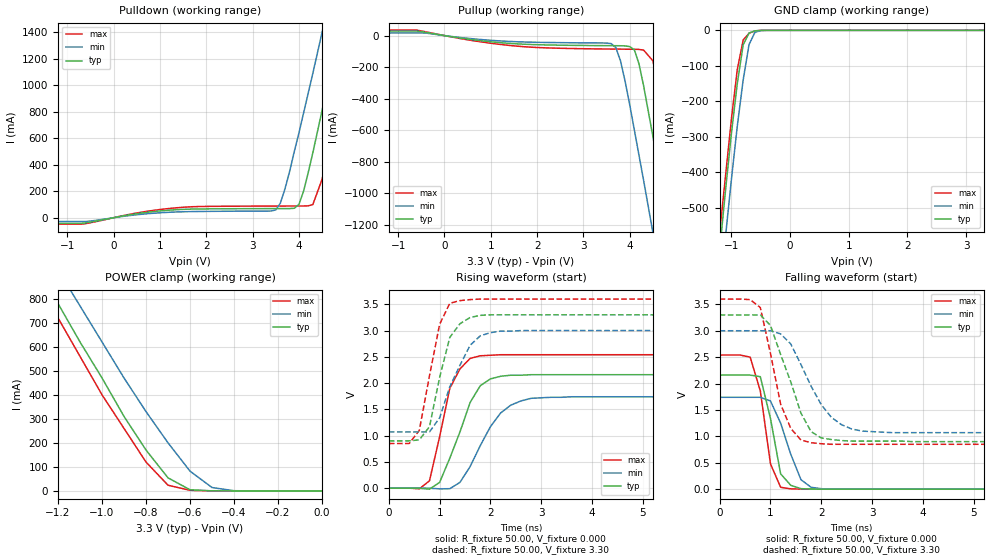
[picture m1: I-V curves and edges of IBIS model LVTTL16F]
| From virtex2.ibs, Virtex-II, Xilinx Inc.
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|   Model LVTTL16F
[Model]   LVTTL16F
Model_type   I/O
Polarity   Non-Inverting
Enable   Active-Low
Vinh = 2.0V
Vinl = 0.8V
Vmeas =   1.40V
Cref =  0pF
Rref =   1.00M
Vref =  0.000V
C_comp   10.00pF   10.00pF   10.00pF
[Temperature Range]   25.00   100.00   0.000
[Voltage Range]   3.30V   3.00V   3.60V
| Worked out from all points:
|   slope of the pulldown table from 0 to 0.495 V, typ, clamps not added: 16.5 ohm
|   slope of the pullup table from 0 to 0.495 V, typ, clamps not added: 22.7 ohm
|   GND clamp passes 1 mA (typ) near -0.57 V on its own axis
|   POWER clamp passes 1 mA (typ) near -0.52 V on its own axis
|   rising waveform, R_fixture 50.00, V_fixture 0.000: 20-80 % time 521ps typ, 612ps min, 384ps max; typ from 0 V to 2.16 V
|   rising waveform, R_fixture 50.00, V_fixture 3.30: 20-80 % time 342ps typ, 505ps min, 328ps max; typ from 0.9 V to 3.3 V
|   falling waveform, R_fixture 50.00, V_fixture 0.000: 20-80 % time 271ps typ, 398ps min, 250ps max; typ from 2.16 V to 0 V
|   falling waveform, R_fixture 50.00, V_fixture 3.30: 20-80 % time 532ps typ, 650ps min, 402ps max; typ from 3.3 V to 0.9 V
[Pulldown]
| voltage   I(typ)   I(min)   I(max)
-3.3V     -42.66mA   -28.71mA   -48.88mA
-700mV    -42.66mA   -28.71mA   -48.88mA
1.3V      59.43mA    42.7mA     73.14mA
3.5V      68.88mA    58.81mA    88.01mA
3.7V      69.04mA    220mA      88.18mA
4V        100mA      640mA      88.42mA
4.3V      490mA      1.09A      98.99mA
4.5V      810mA      1.4A       290mA
4.9V      1.45A      2.03A      910mA
5.1V      1.78A      2.34A      1.24A
5.3V      2.11A      2.66A      1.56A
6.6V      4.28A      4.72A      3.72A
[Pullup]
| voltage   I(typ)   I(min)   I(max)
-3.3V     28.6mA     16.68mA    34.69mA
-600mV    28.6mA     16.68mA    34.69mA
3.6V      -63.99mA   -50.9mA    -85.36mA
3.8V      -64.43mA   -160mA     -85.91mA
4.1V      -90.87mA   -600mA     -86.68mA
4.3V      -320mA     -920mA     -92.25mA
4.5V      -640mA     -1.25A     -160mA
4.7V      -980mA     -1.59A     -440mA
4.9V      -1.32A     -1.93A     -770mA
5.1V      -1.67A     -2.27A     -1.11A
5.3V      -2.02A     -2.61A     -1.46A
6.6V      -4.32A     -4.85A     -3.75A
[GND_clamp]
| voltage   I(typ)   I(min)   I(max)
-3.3V     -4.3A      -4.31A     -4.26A
-1.2V     -620mA     -740mA     -570mA
-1.1V     -450mA     -580mA     -410mA
-1V       -290mA     -420mA     -250mA
-900mV    -150mA     -270mA     -110mA
-800mV    -41.03mA   -140mA     -27.28mA
-700mV    -7.6mA     -40.21mA   -8.18mA
-600mV    -1.42mA    -5.61mA    -1.62mA
-500mV    -130uA     -670uA     -130uA
3.3V      67.85pA    43.48uA    45.6pA
[POWER_clamp]
| voltage   I(typ)   I(min)   I(max)
-3.3V     4.25A      4.22A      4.2A
-1.3V     940mA      1.07A      880mA
-1.2V     780mA      920mA      720mA
-1.1V     620mA      770mA      560mA
-1V       470mA      620mA      400mA
-900mV    310mA      470mA      260mA
-800mV    170mA      330mA      120mA
-700mV    54.34mA    200mA      23.62mA
-600mV    4.76mA     82.21mA    2.52mA
-500mV    280uA      14.02mA    260uA
-400mV    16.9uA     860uA      14.85uA
0V        67.85pA    2.04nA     61.89pA
[Ramp]
| variable   typ   min   max
dV/dt_r   1.29/0.44n   1.04/0.60n   1.52/0.34n
dV/dt_f   1.44/0.46n   1.16/0.64n   1.65/0.35n
R_load = 50.00
[Rising Waveform]
R_fixture = 50.00
V_fixture = 0.000
| time   V(typ)   V(min)   V(max)
0s        0V         0V         0V
600ps     -3.08mV    20.39uV    -12.83mV
800ps     -19.44mV   -1.58mV    140mV
1ns       110mV      -13.7mV    980mV
1.2ns     570mV      -10.5mV    1.9V
1.6ns     1.63V      410mV      2.47V
1.8ns     1.95V      810mV      2.52V
2.2ns     2.13V      1.43V      2.54V
2.8ns     2.16V      1.71V      2.54V
10ns      2.16V      1.74V      2.54V
[Rising Waveform]
R_fixture = 50.00
V_fixture = 3.30
V_fixture_min = 3.00
V_fixture_max = 3.60
| time   V(typ)   V(min)   V(max)
0s        900mV      1.07V      850mV
400ps     900mV      1.07V      850mV
600ps     920mV      1.07V      1.1V
800ps     1.17V      1.07V      2.14V
1ns       2.11V      1.34V      3.12V
1.2ns     2.87V      1.93V      3.52V
1.6ns     3.25V      2.72V      3.59V
1.8ns     3.29V      2.9V       3.6V
2.2ns     3.3V       2.99V      3.6V
10ns      3.3V       3V         3.6V
[Falling Waveform]
R_fixture = 50.00
V_fixture = 0.000
| time   V(typ)   V(min)   V(max)
0s        2.16V      1.74V      2.54V
600ps     2.16V      1.74V      2.5V
800ps     2.13V      1.74V      1.86V
1ns       1.34V      1.67V      480mV
1.2ns     290mV      1.25V      34.97mV
1.4ns     72.7mV     660mV      6.23mV
1.6ns     9.68mV     180mV      1.58mV
1.8ns     2.28mV     35.69mV    600uV
2.4ns     220uV      1.24mV     56.85uV
10ns      1.37uV     2.96uV     4.37uV
[Falling Waveform]
R_fixture = 50.00
V_fixture = 3.30
V_fixture_min = 3.00
V_fixture_max = 3.60
| time   V(typ)   V(min)   V(max)
0s        3.3V       3V         3.6V
800ps     3.3V       3V         3.44V
1ns       3.1V       3V         2.57V
1.2ns     2.55V      2.94V      1.61V
1.4ns     2.03V      2.75V      1.15V
1.6ns     1.44V      2.36V      930mV
1.8ns     1.09V      1.95V      880mV
2.2ns     940mV      1.36V      850mV
2.8ns     910mV      1.1V       850mV
10ns      900mV      1.07V      850mV
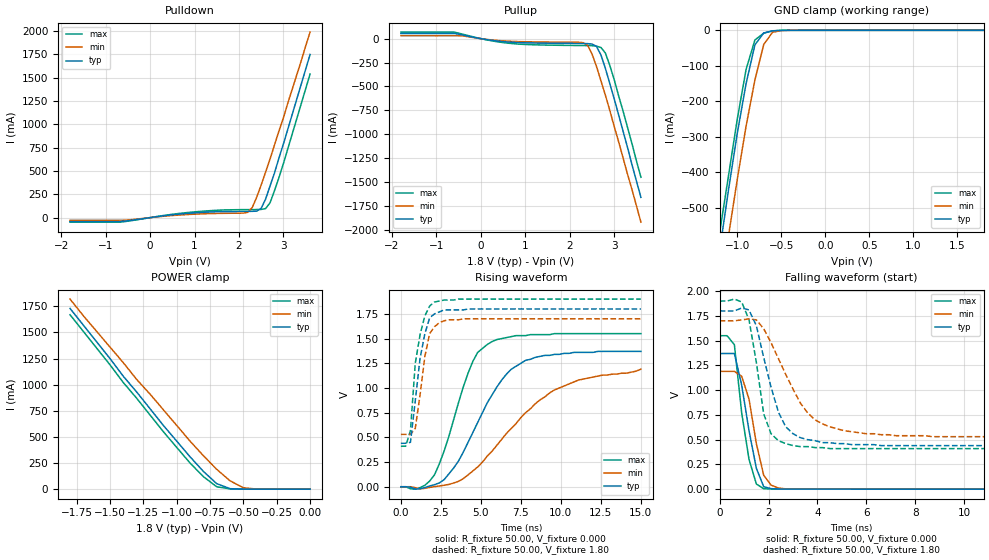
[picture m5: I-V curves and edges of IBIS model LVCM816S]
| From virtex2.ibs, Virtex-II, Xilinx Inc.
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|   Model LVCM816S
[Model]   LVCM816S
Model_type   I/O
Polarity   Non-Inverting
Enable   Active-Low
Vinh = 1.19V
Vinl = 0.4V
Vmeas =   0.90V
Cref =  0pF
Rref =   1.00M
Vref =  0.000V
C_comp   10.00pF   10.00pF   10.00pF
[Temperature Range]   25.00   100.00   0.000
[Voltage Range]   1.80V   1.70V   1.90V
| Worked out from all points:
|   slope of the pulldown table from 0 to 0.27 V, typ, clamps not added: 15.4 ohm
|   slope of the pullup table from 0 to 0.27 V, typ, clamps not added: 14.2 ohm
|   GND clamp passes 1 mA (typ) near -0.57 V on its own axis
|   POWER clamp passes 1 mA (typ) near -0.52 V on its own axis
|   rising waveform, R_fixture 50.00, V_fixture 0.000: 20-80 % time 2.73ns typ, 4.29ns min, 1.84ns max; typ from 0 V to 1.37 V
|   rising waveform, R_fixture 50.00, V_fixture 1.80: 20-80 % time 686ps typ, 637ps min, 637ps max; typ from 0.44 V to 1.8 V
|   falling waveform, R_fixture 50.00, V_fixture 0.000: 20-80 % time 593ps typ, 563ps min, 498ps max; typ from 1.37 V to 0 V
|   falling waveform, R_fixture 50.00, V_fixture 1.80: 20-80 % time 922ps typ, 1.5ns min, 603ps max; typ from 1.8 V to 0.44 V
[Pulldown]
| voltage   I(typ)   I(min)   I(max)
-1.8V     -42.66mA   -28.72mA   -48.89mA
-700mV    -42.66mA   -28.72mA   -48.89mA
900mV     47.73mA    34.88mA    57.36mA
2.2V      67.2mA     56.66mA    86.05mA
2.3V      67.54mA    110mA      86.33mA
2.4V      69.73mA    220mA      86.66mA
2.5V      99.28mA    350mA      87.97mA
2.6V      200mA      490mA      97.08mA
2.7V      340mA      630mA      160mA
2.9V      640mA      930mA      430mA
3V        790mA      1.07A      580mA
3.6V      1.75A      1.99A      1.54A
[Pullup]
| voltage   I(typ)   I(min)   I(max)
-1.8V     54.35mA    30.98mA    68.67mA
-600mV    54.35mA    30.98mA    68.67mA
100mV     -7.7mA     -5.89mA    -9.92mA
700mV     -37.83mA   -28.42mA   -51.54mA
2.2V      -50.35mA   -38.05mA   -71.67mA
2.4V      -51.79mA   -68.88mA   -72.53mA
2.5V      -56.69mA   -160mA     -73.67mA
2.6V      -79.92mA   -290mA     -78.72mA
2.7V      -170mA     -440mA     -91.95mA
2.8V      -310mA     -590mA     -150mA
3V        -630mA     -920mA     -430mA
3.6V      -1.66A     -1.92A     -1.45A
[GND_clamp]
| voltage   I(typ)   I(min)   I(max)
-1.8V     -1.65A     -1.74A     -1.6A
-1.2V     -620mA     -740mA     -570mA
-1.1V     -450mA     -580mA     -410mA
-1V       -290mA     -420mA     -250mA
-900mV    -150mA     -270mA     -110mA
-800mV    -40.97mA   -140mA     -27.17mA
-700mV    -7.54mA    -40.17mA   -8.08mA
-600mV    -1.39mA    -5.57mA    -1.57mA
-500mV    -120uA     -660uA     -120uA
1.8V      34.27pA    98.88nA    22.46pA
[POWER_clamp]
| voltage   I(typ)   I(min)   I(max)
-1.8V     1.73A      1.82A      1.67A
-1.7V     1.57A      1.66A      1.51A
-1.4V     1.08A      1.21A      1.02A
-1.3V     930mA      1.05A      870mA
-1.1V     610mA      760mA      550mA
-900mV    310mA      460mA      250mA
-800mV    170mA      320mA      120mA
-700mV    52.75mA    190mA      22.81mA
-600mV    4.57mA     79.88mA    2.44mA
-500mV    270uA      13.45mA    250uA
-400mV    16.38uA    820uA      14.46uA
0V        34.27pA    1.07nA     29.84pA
[Ramp]
| variable   typ   min   max
dV/dt_r   0.82/2.72n   0.70/4.14n   0.93/1.83n
dV/dt_f   0.82/0.93n   0.70/1.50n   0.90/0.65n
R_load = 50.00
[Rising Waveform]
R_fixture = 50.00
V_fixture = 0.000
| time   V(typ)   V(min)   V(max)
0s        0V         0V         0V
1.2ns     -20.49mV   -22.42mV   -9mV
2.1ns     20.46mV    1.07mV     120mV
3.3ns     190mV      37.59mV    680mV
4.2ns     450mV      120mV      1.15V
5.4ns     850mV      310mV      1.44V
6.6ns     1.14V      540mV      1.51V
7.8ns     1.28V      750mV      1.53V
11.1ns    1.36V      1.08V      1.55V
15ns      1.37V      1.19V      1.55V
[Rising Waveform]
R_fixture = 50.00
V_fixture = 1.80
V_fixture_min = 1.70
V_fixture_max = 1.90
| time   V(typ)   V(min)   V(max)
0s        440mV      530mV      410mV
300ps     440mV      530mV      410mV
600ps     450mV      530mV      570mV
900ps     870mV      590mV      1.25V
1.2ns     1.3V       930mV      1.54V
1.5ns     1.55V      1.32V      1.73V
1.8ns     1.71V      1.55V      1.83V
2.1ns     1.75V      1.62V      1.87V
3.9ns     1.79V      1.7V       1.9V
15ns      1.8V       1.7V       1.9V
[Falling Waveform]
R_fixture = 50.00
V_fixture = 0.000
| time   V(typ)   V(min)   V(max)
0s        1.37V      1.19V      1.55V
300ps     1.37V      1.19V      1.55V
600ps     1.37V      1.19V      1.46V
900ps     1.05V      1.14V      770mV
1.2ns     590mV      910mV      300mV
1.5ns     210mV      460mV      51.81mV
1.8ns     24.76mV    140mV      4.54mV
2.1ns     5.13mV     41.39mV    1.83mV
2.7ns     1.59mV     3.14mV     1.2mV
15ns      -27.08uV   -24.9uV    32.58uV
[Falling Waveform]
R_fixture = 50.00
V_fixture = 1.80
V_fixture_min = 1.70
V_fixture_max = 1.90
| time   V(typ)   V(min)   V(max)
0s        1.8V       1.7V       1.9V
900ps     1.83V      1.71V      1.89V
1.2ns     1.81V      1.72V      1.71V
1.5ns     1.65V      1.71V      1.28V
1.8ns     1.33V      1.62V      760mV
2.1ns     1.03V      1.48V      560mV
2.7ns     630mV      1.16V      460mV
3.6ns     500mV      770mV      430mV
5.1ns     460mV      590mV      410mV
15ns      440mV      530mV      410mV
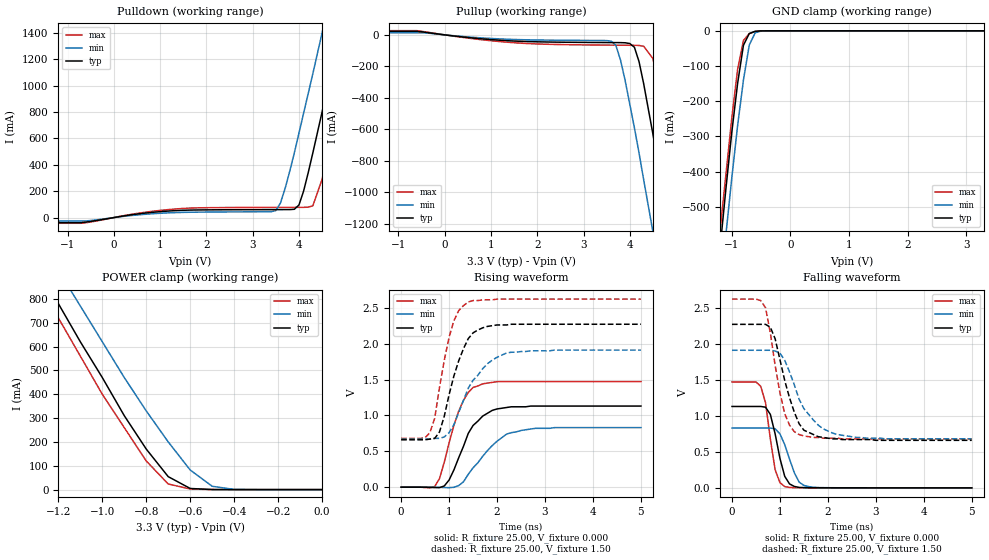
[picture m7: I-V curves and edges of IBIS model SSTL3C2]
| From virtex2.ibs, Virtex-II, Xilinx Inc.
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|   Model SSTL3C2
[Model]   SSTL3C2
Model_type   I/O
Polarity   Non-Inverting
Enable   Active-Low
Vinh = 1.7V
Vinl = 1.3V
Vmeas =   1.50V
Cref =  0pF
Rref =  25.00
Vref =   1.50V
C_comp   10.00pF   10.00pF   10.00pF
[Temperature Range]   25.00   100.00   0.000
[Voltage Range]   3.30V   3.00V   3.60V
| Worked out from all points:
|   slope of the pulldown table from 0 to 0.495 V, typ, clamps not added: 18.7 ohm
|   slope of the pullup table from 0 to 0.495 V, typ, clamps not added: 29.6 ohm
|   GND clamp passes 1 mA (typ) near -0.57 V on its own axis
|   POWER clamp passes 1 mA (typ) near -0.52 V on its own axis
|   rising waveform, R_fixture 25.00, V_fixture 0.000: 20-80 % time 483ps typ, 661ps min, 402ps max; typ from 0 V to 1.13 V
|   rising waveform, R_fixture 25.00, V_fixture 1.50: 20-80 % time 416ps typ, 589ps min, 337ps max; typ from 0.66 V to 2.27 V
|   falling waveform, R_fixture 25.00, V_fixture 0.000: 20-80 % time 231ps typ, 277ps min, 189ps max; typ from 1.13 V to 0 V
|   falling waveform, R_fixture 25.00, V_fixture 1.50: 20-80 % time 400ps typ, 554ps min, 310ps max; typ from 2.27 V to 0.66 V
[Pulldown]
| voltage   I(typ)   I(min)   I(max)
-3.3V     -37.48mA   -25.2mA    -43mA
-700mV    -37.48mA   -25.2mA    -43mA
1.3V      52.15mA    37.43mA    64.25mA
3.5V      60.35mA    53.12mA    77.14mA
3.7V      60.49mA    220mA      77.29mA
4V        95.25mA    640mA      77.5mA
4.3V      490mA      1.09A      89.15mA
4.5V      800mA      1.4A       290mA
4.9V      1.45A      2.02A      910mA
5.1V      1.78A      2.34A      1.23A
5.3V      2.11A      2.65A      1.56A
6.6V      4.27A      4.71A      3.72A
[Pullup]
| voltage   I(typ)   I(min)   I(max)
-3.3V     21.9mA     12.73mA    26.65mA
-600mV    21.9mA     12.73mA    26.65mA
3.6V      -48.95mA   -40.18mA   -65.29mA
3.8V      -49.31mA   -160mA     -65.71mA
4.1V      -78.6mA    -590mA     -66.32mA
4.3V      -310mA     -920mA     -72.41mA
4.5V      -630mA     -1.25A     -150mA
4.7V      -970mA     -1.58A     -430mA
4.9V      -1.32A     -1.92A     -760mA
5.1V      -1.66A     -2.26A     -1.1A
5.3V      -2.01A     -2.6A      -1.45A
6.6V      -4.32A     -4.84A     -3.74A
[GND_clamp]
| voltage   I(typ)   I(min)   I(max)
-3.3V     -4.3A      -4.31A     -4.26A
-1.2V     -620mA     -740mA     -570mA
-1.1V     -450mA     -580mA     -410mA
-1V       -290mA     -420mA     -250mA
-900mV    -150mA     -270mA     -110mA
-800mV    -41.03mA   -140mA     -27.28mA
-700mV    -7.6mA     -40.21mA   -8.18mA
-600mV    -1.42mA    -5.61mA    -1.62mA
-500mV    -130uA     -670uA     -130uA
3.3V      67.85pA    43.48uA    45.6pA
[POWER_clamp]
| voltage   I(typ)   I(min)   I(max)
-3.3V     4.25A      4.22A      4.2A
-1.3V     940mA      1.07A      880mA
-1.2V     780mA      920mA      720mA
-1.1V     620mA      770mA      560mA
-1V       470mA      620mA      400mA
-900mV    310mA      470mA      260mA
-800mV    170mA      330mA      120mA
-700mV    54.34mA    200mA      23.62mA
-600mV    4.76mA     82.21mA    2.52mA
-500mV    280uA      14.02mA    260uA
-400mV    16.9uA     860uA      14.85uA
0V        67.85pA    2.04nA     61.89pA
[Ramp]
| variable   typ   min   max
dV/dt_r   0.68/0.48n   0.50/0.64n   0.88/0.40n
dV/dt_f   0.87/0.68n   0.63/0.87n   1.10/0.56n
R_load = 25.00
[Rising Waveform]
R_fixture = 25.00
V_fixture = 0.000
| time   V(typ)   V(min)   V(max)
0s        0V         0V         0V
700ps     -5.87mV    -400uV     9.95mV
800ps     -6.42mV    -1.93mV    120mV
1ns       100mV      -7.22mV    620mV
1.2ns     410mV      21.53mV    1.06V
1.5ns     860mV      270mV      1.39V
1.9ns     1.07V      580mV      1.46V
2.3ns     1.12V      760mV      1.47V
2.8ns     1.13V      820mV      1.47V
5ns       1.13V      830mV      1.47V
[Rising Waveform]
R_fixture = 25.00
V_fixture = 1.50
V_fixture_min = 1.30
V_fixture_max = 1.70
| time   V(typ)   V(min)   V(max)
0s        660mV      670mV      680mV
600ps     670mV      670mV      760mV
700ps     680mV      680mV      960mV
800ps     770mV      680mV      1.39V
1ns       1.29V      760mV      2.09V
1.1ns     1.55V      870mV      2.32V
1.4ns     2.07V      1.38V      2.58V
1.8ns     2.24V      1.72V      2.61V
2.2ns     2.26V      1.87V      2.62V
5ns       2.27V      1.91V      2.62V
[Falling Waveform]
R_fixture = 25.00
V_fixture = 0.000
| time   V(typ)   V(min)   V(max)
0s        1.13V      830mV      1.47V
600ps     1.13V      830mV      1.41V
700ps     1.12V      830mV      1.18V
800ps     1.02V      830mV      680mV
900ps     750mV      820mV      250mV
1ns       410mV      750mV      72.81mV
1.1ns     160mV      600mV      18.13mV
1.4ns     6.22mV     80.2mV     1.86mV
1.6ns     2.37mV     17.29mV    1.05mV
5ns       -2.39uV    3.98uV     -1.52uV
[Falling Waveform]
R_fixture = 25.00
V_fixture = 1.50
V_fixture_min = 1.30
V_fixture_max = 1.70
| time   V(typ)   V(min)   V(max)
0s        2.27V      1.91V      2.62V
500ps     2.27V      1.91V      2.62V
700ps     2.27V      1.91V      2.5V
900ps     2.07V      1.9V       1.7V
1.1ns     1.49V      1.77V      1.03V
1.2ns     1.25V      1.61V      870mV
1.4ns     890mV      1.23V      740mV
1.8ns     710mV      870mV      700mV
2.2ns     680mV      740mV      690mV
5ns       660mV      680mV      680mV
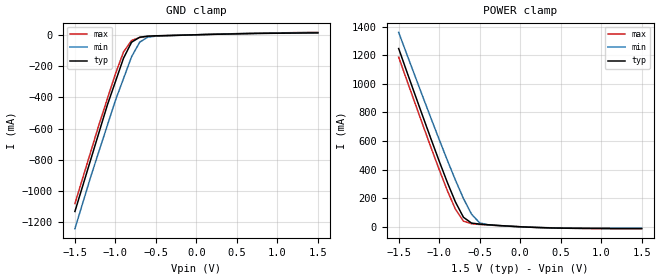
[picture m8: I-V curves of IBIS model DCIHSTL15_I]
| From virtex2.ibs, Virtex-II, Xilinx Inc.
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|   Model DCIHSTL15_I
[Model]   DCIHSTL15_I
Model_type   Input
Vinh = 0.85V
Vinl = 0.65V
Polarity   Non-Inverting
C_comp   10.00pF   10.00pF   10.00pF
[Temperature Range]   25.00   100.00   0.000
[Voltage Range]   1.50V   1.40V   1.60V
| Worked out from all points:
|   GND clamp passes 1 mA (typ) near -0.07 V on its own axis
|   POWER clamp passes 1 mA (typ) near -0.03 V on its own axis
[GND_clamp]
| voltage   I(typ)   I(min)   I(max)
-1.5V     -1.13A     -1.24A     -1.08A
-1.3V     -790mA     -900mA     -740mA
-1.2V     -620mA     -740mA     -570mA
-1.1V     -450mA     -580mA     -410mA
-1V       -300mA     -420mA     -250mA
-900mV    -150mA     -280mA     -110mA
-800mV    -47.37mA   -140mA     -36.18mA
-700mV    -15.74mA   -47.4mA    -17.57mA
-600mV    -8.92mA    -14.7mA    -10.22mA
-500mV    -6.58mA    -8.81mA    -7.55mA
500mV     5.88mA     7.18mA     6.98mA
1.5V      12.03mA    14.2mA     15.15mA
[POWER_clamp]
| voltage   I(typ)   I(min)   I(max)
-1.5V     1.247A     1.36A      1.187A
-1.2V     769.1mA    906.7mA    709.2mA
-1V       459.7mA    610.9mA    400.5mA
-900mV    311.6mA    466.9mA    254.3mA
-800mV    174.3mA    327.7mA    123.5mA
-700mV    66.3mA     197.6mA    39.38mA
-600mV    25.61mA    88.12mA    21.07mA
-500mV    18.6mA     27.17mA    15.92mA
-400mV    14.29mA    13.69mA    12.3mA
200mV     -5.021mA   -4.418mA   -4.645mA
1.5V      -13.01mA   -11.16mA   -13.3mA
